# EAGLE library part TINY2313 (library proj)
ATTiny2313

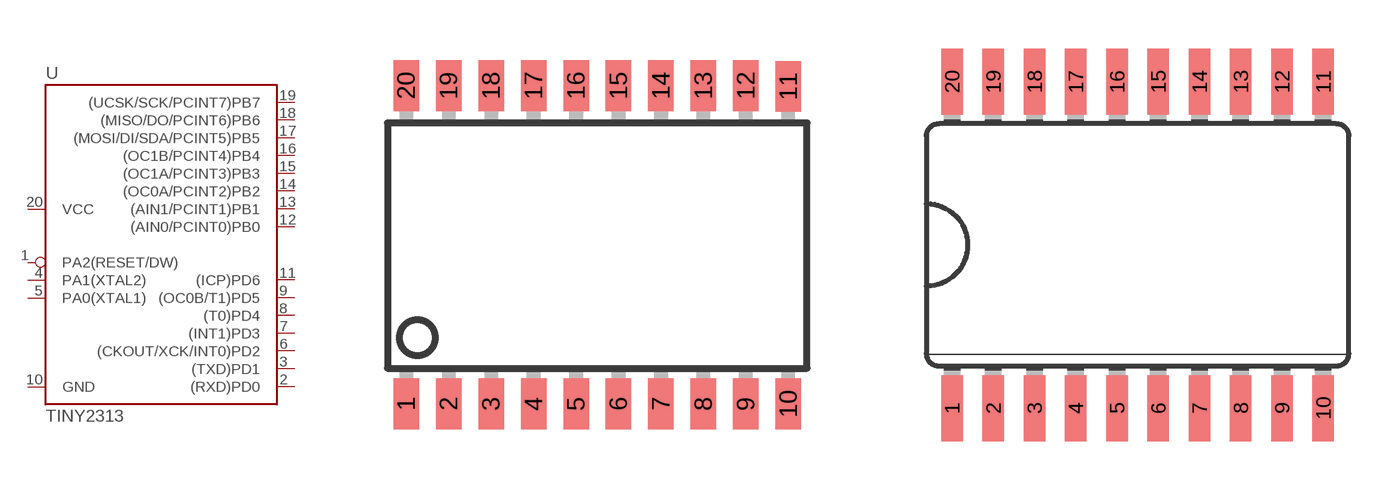
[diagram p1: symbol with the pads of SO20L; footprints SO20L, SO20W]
Designator prefix -

## TINY2313S  [SO20L]
1  PA2(RESET/DW)
2  (RXD)PD0
3  (TXD)PD1
4  PA1(XTAL2)
5  PA0(XTAL1)
6  (CKOUT/XCK/INT0)PD2
7  (INT1)PD3
8  (T0)PD4
9  (OC0B/T1)PD5
10  GND  pwr
11  (ICP)PD6
12  (AIN0/PCINT0)PB0
13  (AIN1/PCINT1)PB1
14  (OC0A/PCINT2)PB2
15  (OC1A/PCINT3)PB3
16  (OC1B/PCINT4)PB4
17  (MOSI/DI/SDA/PCINT5)PB5
18  (MISO/DO/PCINT6)PB6
19  (UCSK/SCK/PCINT7)PB7
20  VCC  pwr

## TINY2313W  [SO20W]
Pads as for SO20L

## Footprint SO20L (pad centres in mm)
Small Outline Package SOIC 0.300"
smd 0.762 x 1.524: 1 -5.715,-4.75; 2 -4.445,-4.75; 3 -3.175,-4.75; 4 -1.905,-4.75; 5 -0.635,-4.75; 6 0.635,-4.75; 7 1.905,-4.75; 8 3.175,-4.75; 9 4.445,-4.75; 10 5.715,-4.75; 11 5.715,4.75; 12 4.445,4.775; 13 3.175,4.775; 14 1.905,4.775; 15 0.635,4.775; 16 -0.635,4.775; 17 -1.905,4.775; 18 -3.175,4.775; 19 -4.445,4.775; 20 -5.715,4.775

## Footprint SO20W (pad centres in mm)
Wide Small Outline package 300 mil
smd 0.66 x 2.032: 1 -5.715,-5.029; 2 -4.445,-5.029; 3 -3.175,-5.029; 4 -1.905,-5.029; 5 -0.635,-5.029; 6 0.635,-5.029; 7 1.905,-5.029; 8 3.175,-5.029; 9 4.445,-5.029; 10 5.715,-5.029; 11 5.715,5.029; 12 4.445,5.029; 13 3.175,5.029; 14 1.905,5.029; 15 0.635,5.029; 16 -0.635,5.029; 17 -1.905,5.029; 18 -3.175,5.029; 19 -4.445,5.029; 20 -5.715,5.029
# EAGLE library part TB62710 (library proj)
Toshiba LED driver - 8-bit constant current source

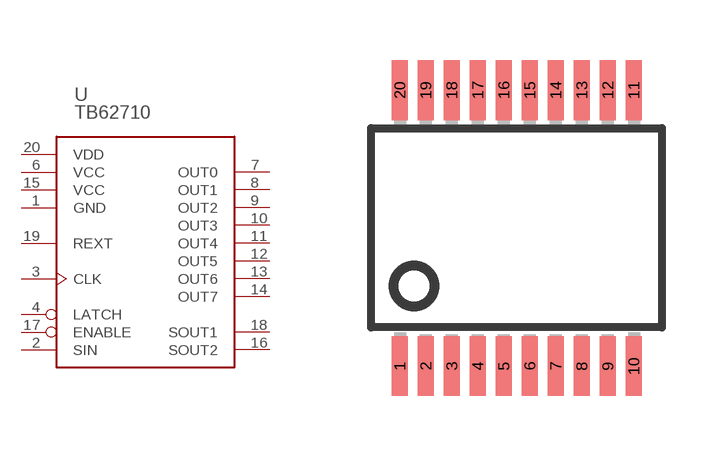
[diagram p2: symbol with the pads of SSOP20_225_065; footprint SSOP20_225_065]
Designator prefix -

## TB62710  [SSOP20_225_065]
1  GND
2  SIN
3  CLK
4  LATCH
6  VCC
7  OUT0
8  OUT1
9  OUT2
10  OUT3
11  OUT4
12  OUT5
13  OUT6
14  OUT7
15  VCC
16  SOUT2
17  ENABLE
18  SOUT1
19  REXT
20  VDD

## Footprint SSOP20_225_065 (pad centres in mm)
Toshiba package
smd 0.4 x 1.5: 1 -3.01,-3.44; 2 -2.36,-3.44; 3 -1.71,-3.44; 4 -1.06,-3.44; 5 -0.41,-3.44; 6 0.24,-3.44; 7 0.89,-3.44; 8 1.54,-3.44; 9 2.19,-3.44; 10 2.84,-3.44; 11 2.84,3.46; 12 2.19,3.46; 13 1.54,3.46; 14 0.89,3.46; 15 0.24,3.46; 16 -0.41,3.46; 17 -1.06,3.46; 18 -1.71,3.46; 19 -2.36,3.46; 20 -3.01,3.46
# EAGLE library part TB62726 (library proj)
LED driver - 16-bit constant current sink Toshiba TB62726 ST-micro STP16C596

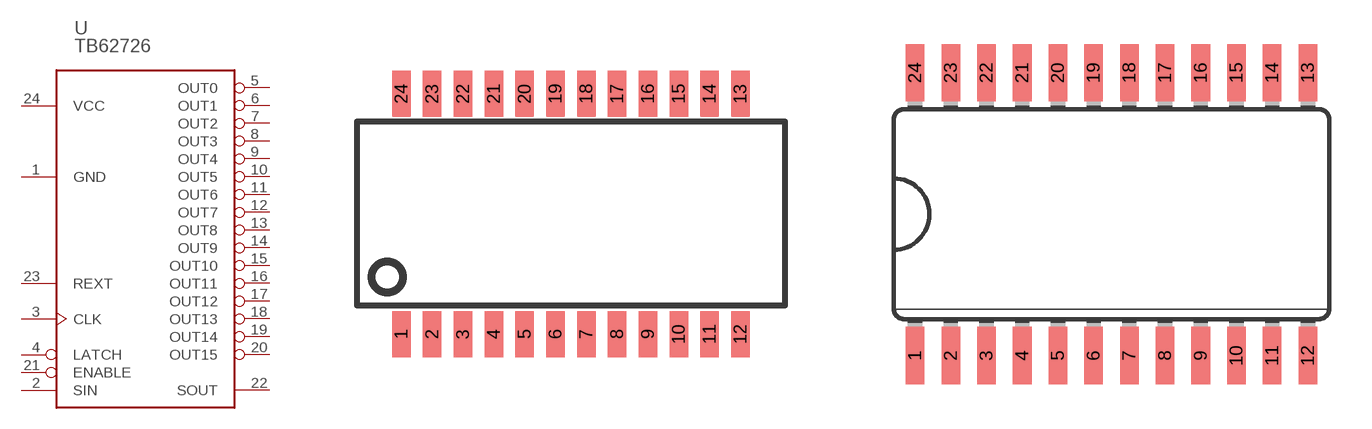
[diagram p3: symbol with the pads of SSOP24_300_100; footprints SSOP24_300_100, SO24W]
Designator prefix -

## TB62726SSOP24  [SSOP24_300_100]
1  GND
2  SIN
3  CLK
4  LATCH
5  OUT0
6  OUT1
7  OUT2
8  OUT3
9  OUT4
10  OUT5
11  OUT6
12  OUT7
13  OUT8
14  OUT9
15  OUT10
16  OUT11
17  OUT12
18  OUT13
19  OUT14
20  OUT15
21  ENABLE
22  SOUT
23  REXT
24  VCC

## TB62726SO24  [SO24W]
Pads as for SSOP24_300_100

## TB62726TSSOP24XP  [TSSOP24_XPAD]
Pads as for SSOP24_300_100

## Footprint SSOP24_300_100 (pad centres in mm)
Toshiba package
smd 0.6 x 1.5: 1 -5.5,-3.9; 2 -4.5,-3.9; 3 -3.5,-3.9; 4 -2.5,-3.9; 5 -1.5,-3.9; 6 -0.5,-3.9; 7 0.5,-3.9; 8 1.5,-3.9; 9 2.5,-3.9; 10 3.5,-3.9; 11 4.5,-3.9; 12 5.5,-3.9; 13 5.5,3.9; 14 4.5,3.9; 15 3.5,3.9; 16 2.5,3.9; 17 1.5,3.9; 18 0.5,3.9; 19 -0.5,3.9; 20 -1.5,3.9; 21 -2.5,3.9; 22 -3.5,3.9; 23 -4.5,3.9; 24 -5.5,3.9

## Footprint SO24W (pad centres in mm)
Wide Small Outline package 300 mil
smd 0.66 x 2.032: 1 -6.985,-5.029; 2 -5.715,-5.029; 3 -4.445,-5.029; 4 -3.175,-5.029; 5 -1.905,-5.029; 6 -0.635,-5.029; 7 0.635,-5.029; 8 1.905,-5.029; 9 3.175,-5.029; 10 4.445,-5.029; 11 5.715,-5.029; 12 6.985,-5.029; 13 6.985,5.029; 14 5.715,5.029; 15 4.445,5.029; 16 3.175,5.029; 17 1.905,5.029; 18 0.635,5.029; 19 -0.635,5.029; 20 -1.905,5.029; 21 -3.175,5.029; 22 -4.445,5.029; 23 -5.715,5.029; 24 -6.985,5.029

## Footprint TSSOP24_XPAD (pad centres in mm)
ST-micro TSSOP24 exposed pad
smd 0.3 x 1: 1 -3.575,-2.9; 2 -2.925,-2.9; 3 -2.275,-2.9; 4 -1.625,-2.9; 5 -0.975,-2.9; 6 -0.325,-2.9; 7 0.325,-2.9; 8 0.975,-2.9; 9 1.625,-2.9; 10 2.275,-2.9; 11 2.925,-2.9; 12 3.575,-2.9; 13 3.575,2.9; 14 2.925,2.9; 15 2.275,2.9; 16 1.625,2.9; 17 0.975,2.9; 18 0.325,2.9; 19 -0.325,2.9; 20 -0.975,2.9; 21 -1.625,2.9; 22 -2.275,2.9; 23 -2.925,2.9; 24 -3.575,2.9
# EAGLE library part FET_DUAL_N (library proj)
Fairchild dual N fet

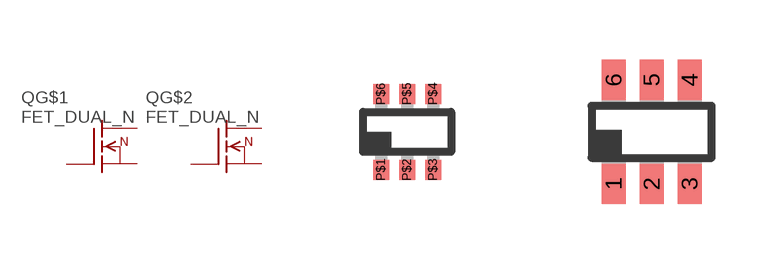
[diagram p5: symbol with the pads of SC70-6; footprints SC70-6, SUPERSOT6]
Designator prefix Q; gates G$1=NFET G$2=NFET

## FET_DUAL_NSC70-6  [SC70-6]
P$1  G$1:SN  pas
P$2  G$1:GN  pas
P$3  G$2:DN  pas
P$4  G$2:SN  pas
P$5  G$2:GN  pas
P$6  G$1:DN  pas

## FET_DUAL_NSOT6  [SUPERSOT6]
1  G$1:GN  pas
2  G$2:SN  pas
3  G$2:GN  pas
4  G$2:DN  pas
5  G$1:SN  pas
6  G$1:DN  pas

## Footprint SC70-6 (pad centres in mm)
Fairchild SC70-6
smd 0.4 x 0.5: P$1 -0.65,-0.95; P$2 0,-0.95; P$3 0.65,-0.95; P$4 0.65,0.95; P$5 0,0.95; P$6 -0.65,0.95

## Footprint SUPERSOT6 (pad centres in mm)
Fairchild SuperSOT6
smd 0.6 x 1: 1 -0.95,-1.3; 2 0,-1.3; 3 0.95,-1.3; 4 0.95,1.3; 5 0,1.3; 6 -0.95,1.3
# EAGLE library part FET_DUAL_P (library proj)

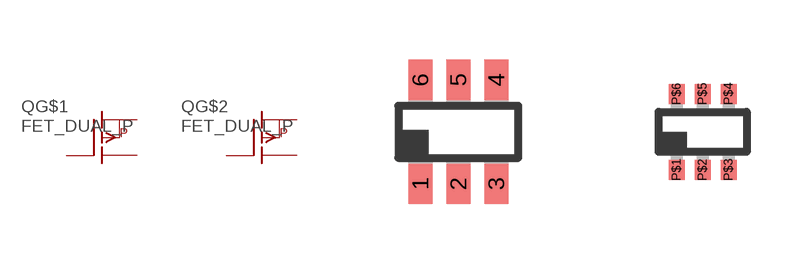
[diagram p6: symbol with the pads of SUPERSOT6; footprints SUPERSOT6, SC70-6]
Designator prefix Q; gates G$1=PFET G$2=PFET

## FET_DUAL_PSOT6  [SUPERSOT6]
1  G$1:GP  pas
2  G$2:SP  pas
3  G$2:GP  pas
4  G$2:DP  pas
5  G$1:SP  pas
6  G$1:DP  pas

## FET_DUAL_PSC70-6  [SC70-6]
P$1  G$1:SP  pas
P$2  G$1:GP  pas
P$3  G$2:DP  pas
P$4  G$2:SP  pas
P$5  G$2:GP  pas
P$6  G$1:DP  pas

## Footprint SUPERSOT6 (pad centres in mm)
Fairchild SuperSOT6
smd 0.6 x 1: 1 -0.95,-1.3; 2 0,-1.3; 3 0.95,-1.3; 4 0.95,1.3; 5 0,1.3; 6 -0.95,1.3

## Footprint SC70-6 (pad centres in mm)
Fairchild SC70-6
smd 0.4 x 0.5: P$1 -0.65,-0.95; P$2 0,-0.95; P$3 0.65,-0.95; P$4 0.65,0.95; P$5 0,0.95; P$6 -0.65,0.95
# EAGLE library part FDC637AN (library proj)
Fairchild FDC637AN power NFET. MUST CONNECT PINS 1,2,5,6 TO DRAIN

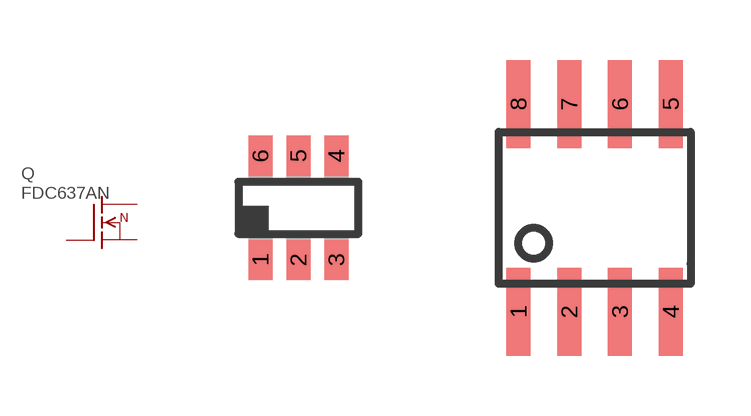
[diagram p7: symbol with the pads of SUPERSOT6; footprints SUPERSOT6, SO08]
Designator prefix Q

## FDC637ANSOT6  [SUPERSOT6]
1  DN  pas
2  DN  pas
3  GN  pas
4  SN  pas
5  DN  pas
6  DN  pas

## FDC637AN  [SO08]

## Footprint SUPERSOT6 (pad centres in mm)
Fairchild SuperSOT6
smd 0.6 x 1: 1 -0.95,-1.3; 2 0,-1.3; 3 0.95,-1.3; 4 0.95,1.3; 5 0,1.3; 6 -0.95,1.3

## Footprint SO08 (pad centres in mm)
Small Outline Package
smd 0.6 x 2.2: 1 -1.905,-2.6; 2 -0.635,-2.6; 3 0.635,-2.6; 4 1.905,-2.6; 5 1.905,2.6; 6 0.635,2.6; 7 -0.635,2.6; 8 -1.905,2.6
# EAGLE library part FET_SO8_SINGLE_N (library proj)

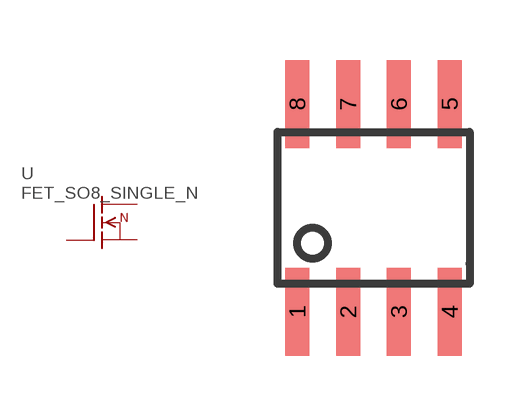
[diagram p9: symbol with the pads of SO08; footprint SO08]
Designator prefix -

## FET_SO8_SINGLE_N  [SO08]
1  SN  pas
2  SN  pas
3  SN  pas
4  GN  pas
5  DN  pas
6  DN  pas
7  DN  pas
8  DN  pas

## Footprint SO08 (pad centres in mm)
Small Outline Package
smd 0.6 x 2.2: 1 -1.905,-2.6; 2 -0.635,-2.6; 3 0.635,-2.6; 4 1.905,-2.6; 5 1.905,2.6; 6 0.635,2.6; 7 -0.635,2.6; 8 -1.905,2.6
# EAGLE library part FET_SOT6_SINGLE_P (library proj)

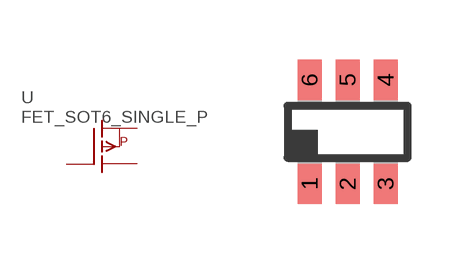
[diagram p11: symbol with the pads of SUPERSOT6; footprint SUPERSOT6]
Designator prefix -

## FET_SOT6_SINGLE_P  [SUPERSOT6]
1  DN  pas
2  DN  pas
3  GN  pas
4  SN  pas
5  DN  pas
6  DN  pas

## Footprint SUPERSOT6 (pad centres in mm)
Fairchild SuperSOT6
smd 0.6 x 1: 1 -0.95,-1.3; 2 0,-1.3; 3 0.95,-1.3; 4 0.95,1.3; 5 0,1.3; 6 -0.95,1.3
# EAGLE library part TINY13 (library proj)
MICROCONTROLLER 1 Kbytes FLASH 64 bytes EEPROM

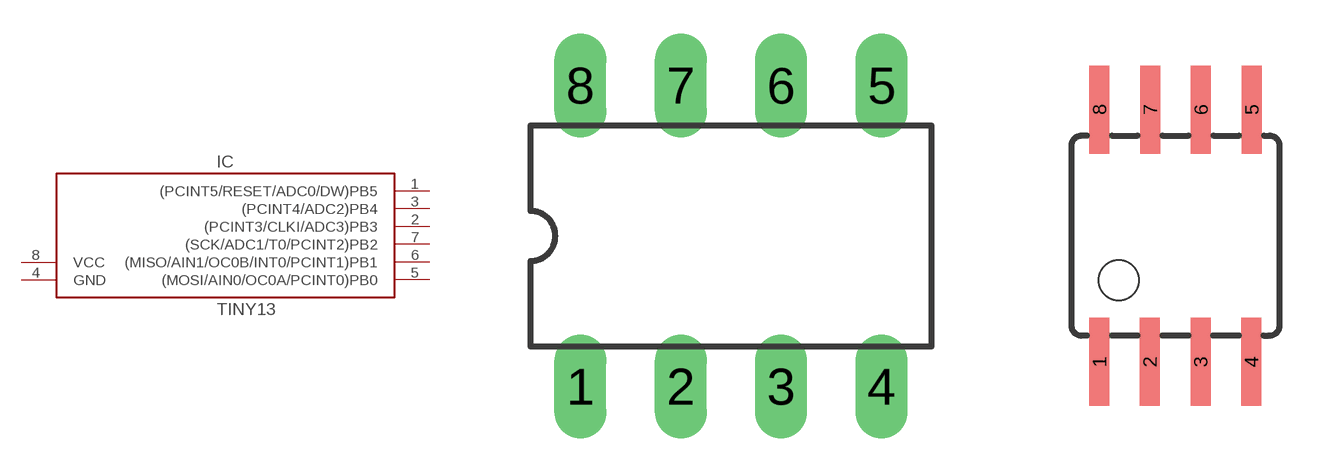
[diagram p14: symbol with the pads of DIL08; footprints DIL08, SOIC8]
Designator prefix IC

## TINY13P  [DIL08]
1  (PCINT5/RESET/ADC0/DW)PB5
2  (PCINT3/CLKI/ADC3)PB3
3  (PCINT4/ADC2)PB4
4  GND  pwr
5  (MOSI/AIN0/OC0A/PCINT0)PB0
6  (MISO/AIN1/OC0B/INT0/PCINT1)PB1
7  (SCK/ADC1/T0/PCINT2)PB2
8  VCC  pwr

## TINY13S  [SOIC8]
Pads as for DIL08

## TINY13S2  [SO08]
Pads as for DIL08

## Footprint DIL08 (pad centres in mm)
Dual In Line
drill 0.813 long: 1 -3.81,-3.81; 2 -1.27,-3.81; 3 1.27,-3.81; 4 3.81,-3.81; 5 3.81,3.81; 6 1.27,3.81; 7 -1.27,3.81; 8 -3.81,3.81

## Footprint SOIC8 (pad centres in mm)
Wide Plastic Gull Wing Small Outline Package
smd 0.5 x 2.2: 1 -1.905,-3.154; 2 -0.645,-3.154; 3 0.625,-3.154; 4 1.895,-3.154; 5 1.905,3.154; 6 0.635,3.154; 7 -0.635,3.154; 8 -1.905,3.154

## Footprint SO08 (pad centres in mm)
Small Outline Package
smd 0.6 x 2.2: 1 -1.905,-2.6; 2 -0.635,-2.6; 3 0.635,-2.6; 4 1.905,-2.6; 5 1.905,2.6; 6 0.635,2.6; 7 -0.635,2.6; 8 -1.905,2.6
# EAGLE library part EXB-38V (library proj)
Panasonic 4 x 0603 resistor array

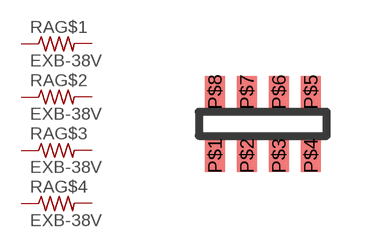
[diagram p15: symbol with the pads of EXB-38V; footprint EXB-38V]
Designator prefix RA; gates G$1=R-US-1 G$2=R-US-1 G$3=R-US-1 G$4=R-US-1

## EXB-38V  [EXB-38V]
P$1  G$1:1  pas
P$2  G$2:1  pas
P$3  G$3:1  pas
P$4  G$4:1  pas
P$5  G$4:2  pas
P$6  G$3:2  pas
P$7  G$2:2  pas
P$8  G$1:2  pas

## Footprint EXB-38V (pad centres in mm)
Panasonic 4 x 0603 resistor array
smd 0.5 x 0.8: P$1 -1.2,-0.8; P$2 -0.4,-0.8; P$3 0.4,-0.8; P$4 1.2,-0.8; P$5 1.2,0.8; P$6 0.4,0.8; P$7 -0.4,0.8; P$8 -1.2,0.8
